VERSION 5.7 ;
  NOWIREEXTENSIONATPIN ON ;
  DIVIDERCHAR "/" ;
  BUSBITCHARS "[]" ;
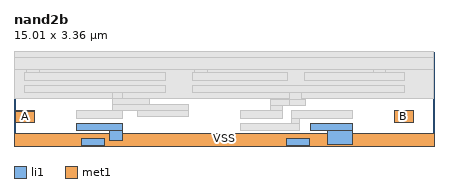
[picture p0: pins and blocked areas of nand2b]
MACRO nand2b
  CLASS BLOCK ;
  FOREIGN nand2b ;
  ORIGIN 6.000 1.650 ;
  SIZE 15.010 BY 3.360 ;
  PIN A
    ANTENNAGATEAREA 1.014000 ;
    PORT
      LAYER li1 ;
        RECT -5.940 -0.820 -5.260 -0.390 ;
      LAYER met1 ;
        RECT -5.930 -0.810 -5.270 -0.400 ;
    END
  END A
  PIN B
    ANTENNAGATEAREA 0.768000 ;
    PORT
      LAYER li1 ;
        RECT 7.590 -0.820 8.270 -0.390 ;
      LAYER met1 ;
        RECT 7.590 -0.820 8.270 -0.390 ;
    END
  END B
  PIN VSS
    ANTENNADIFFAREA 1.353600 ;
    PORT
      LAYER li1 ;
        RECT -3.780 -1.110 -2.120 -0.830 ;
        RECT 4.580 -1.110 6.080 -0.830 ;
        RECT -3.580 -1.630 -2.760 -1.390 ;
        RECT -2.580 -1.450 -2.130 -1.110 ;
        RECT 3.740 -1.630 4.560 -1.390 ;
        RECT 5.200 -1.610 6.080 -1.110 ;
      LAYER met1 ;
        RECT -6.000 -1.650 9.010 -1.200 ;
    END
  END VSS
  OBS
      LAYER nwell ;
        RECT -6.000 0.060 9.000 1.710 ;
      LAYER li1 ;
        RECT -5.540 0.980 -5.090 1.320 ;
        RECT -3.590 1.260 -2.770 1.500 ;
        RECT 0.460 0.990 0.910 1.320 ;
        RECT 2.290 1.260 3.110 1.500 ;
        RECT 6.840 0.990 7.290 1.320 ;
        RECT 0.460 0.980 1.480 0.990 ;
        RECT 6.840 0.980 7.860 0.990 ;
        RECT -5.630 0.700 -0.570 0.980 ;
        RECT 0.380 0.700 3.760 0.980 ;
        RECT 4.380 0.700 7.960 0.980 ;
        RECT -5.630 0.250 -0.570 0.530 ;
        RECT 0.380 0.250 7.960 0.530 ;
        RECT -2.470 0.040 -2.120 0.250 ;
        RECT -2.470 -0.150 -1.140 0.040 ;
        RECT 3.840 0.020 4.290 0.250 ;
        RECT -2.470 -0.370 0.220 -0.150 ;
        RECT -2.470 -0.380 -2.120 -0.370 ;
        RECT -3.780 -0.660 -2.120 -0.380 ;
        RECT -1.600 -0.580 0.220 -0.370 ;
        RECT 3.160 -0.220 4.410 0.020 ;
        RECT 3.160 -0.380 3.610 -0.220 ;
        RECT 2.110 -0.660 3.610 -0.380 ;
        RECT 4.580 -0.390 6.080 -0.380 ;
        RECT 3.920 -0.660 6.080 -0.390 ;
        RECT 2.110 -0.840 3.610 -0.830 ;
        RECT 3.920 -0.840 4.210 -0.660 ;
        RECT 2.110 -1.110 4.210 -0.840 ;
      LAYER met1 ;
        RECT -6.000 1.070 9.000 1.520 ;
        RECT 3.840 -0.220 4.410 0.020 ;
  END
END nand2b
END LIBRARY

